VERSION 5.8 ;
BUSBITCHARS "[]" ;
DIVIDERCHAR "/" ;

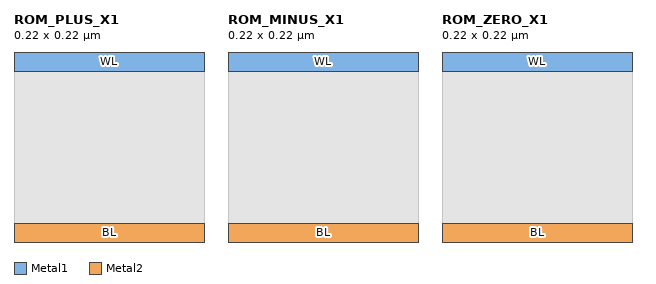
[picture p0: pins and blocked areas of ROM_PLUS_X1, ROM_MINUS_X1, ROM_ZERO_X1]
MACRO ROM_PLUS_X1
  CLASS CORE ;
  SIZE 0.2200 BY 0.2200 ;
  SYMMETRY X Y ;

  PIN WL
    DIRECTION INPUT ;
    USE SIGNAL ;
    PORT
      LAYER Metal1 ;
        RECT 0.0000 0.1980 0.2200 0.2200 ;
    END
  END WL

  PIN BL
    DIRECTION OUTPUT ;
    USE SIGNAL ;
    PORT
      LAYER Metal2 ;
        RECT 0.0000 0.0000 0.2200 0.0220 ;
    END
  END BL

  OBS
    LAYER Metal1 ;
      RECT 0.0000 0.0000 0.2200 0.1980 ;
    LAYER Metal2 ;
      RECT 0.0000 0.0220 0.2200 0.2200 ;
  END

END ROM_PLUS_X1

MACRO ROM_MINUS_X1
  CLASS CORE ;
  SIZE 0.2200 BY 0.2200 ;
  SYMMETRY X Y ;

  PIN WL
    DIRECTION INPUT ;
    USE SIGNAL ;
    PORT
      LAYER Metal1 ;
        RECT 0.0000 0.1980 0.2200 0.2200 ;
    END
  END WL

  PIN BL
    DIRECTION OUTPUT ;
    USE SIGNAL ;
    PORT
      LAYER Metal2 ;
        RECT 0.0000 0.0000 0.2200 0.0220 ;
    END
  END BL

  OBS
    LAYER Metal1 ;
      RECT 0.0000 0.0000 0.2200 0.1980 ;
    LAYER Metal2 ;
      RECT 0.0000 0.0220 0.2200 0.2200 ;
  END

END ROM_MINUS_X1

MACRO ROM_ZERO_X1
  CLASS CORE ;
  SIZE 0.2200 BY 0.2200 ;
  SYMMETRY X Y ;

  PIN WL
    DIRECTION INPUT ;
    USE SIGNAL ;
    PORT
      LAYER Metal1 ;
        RECT 0.0000 0.1980 0.2200 0.2200 ;
    END
  END WL

  PIN BL
    DIRECTION OUTPUT ;
    USE SIGNAL ;
    PORT
      LAYER Metal2 ;
        RECT 0.0000 0.0000 0.2200 0.0220 ;
    END
  END BL

  OBS
    LAYER Metal1 ;
      RECT 0.0000 0.0000 0.2200 0.1980 ;
    LAYER Metal2 ;
      RECT 0.0000 0.0220 0.2200 0.2200 ;
  END

END ROM_ZERO_X1

END LIBRARY
